VERSION 5.8 ;
BUSBITCHARS "[]" ;
DIVIDERCHAR "/" ;
MANUFACTURINGGRID 0.05 ;

UNITS
    DATABASE MICRONS 1000 ;
END UNITS

SITE CoreSite
    CLASS CORE ;
    SIZE 5.400 BY 64.800 ;
END CoreSite

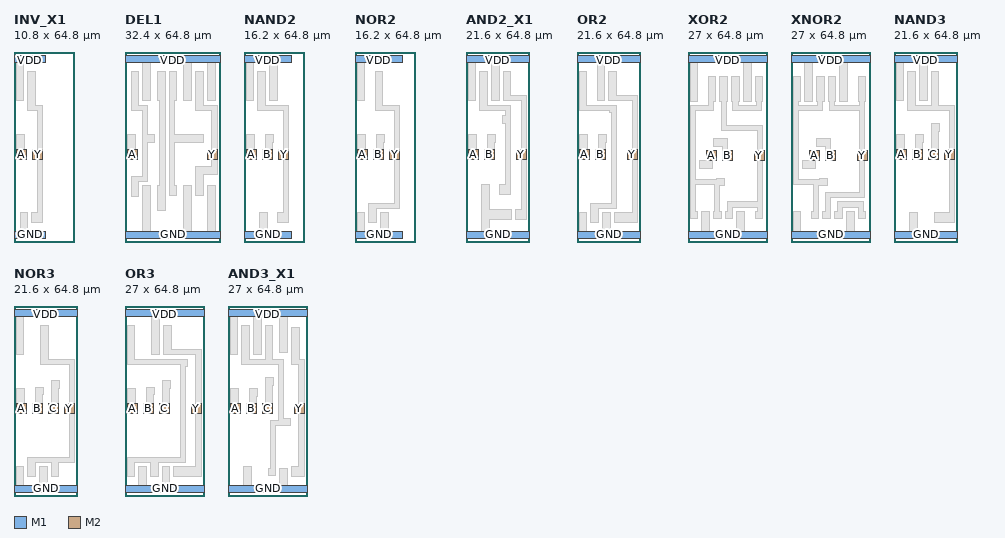
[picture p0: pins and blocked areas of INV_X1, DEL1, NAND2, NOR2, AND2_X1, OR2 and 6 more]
MACRO INV_X1
    CLASS CORE ;
    FOREIGN INV_X1 0.0 0.0 ;
    ORIGIN 0.0 0.0 ;
    SIZE 10.800 BY 64.800 ;
    SITE CoreSite ;

    PIN GND
        DIRECTION INOUT ;
        USE GROUND ;
        PORT
            LAYER M1 ;
                RECT 0.000 1.100 10.800 3.700 ;
        END
    END GND

    PIN VDD
        DIRECTION INOUT ;
        USE POWER ;
        PORT
            LAYER M1 ;
                RECT 0.000 61.100 10.800 63.700 ;
        END
    END VDD

    PIN A
        DIRECTION INPUT ;
        USE SIGNAL ;
        PORT
            LAYER M2 ;
                RECT 1.000 28.000 4.400 31.400 ;
        END
    END A

    PIN Y
        DIRECTION OUTPUT ;
        USE SIGNAL ;
        PORT
            LAYER M2 ;
                RECT 6.400 28.000 9.800 31.400 ;
        END
    END Y

    OBS
        LAYER M1 ;
            POLYGON 2.100 3.700  2.100 9.900  4.700 9.900  4.700 3.700 ;
            POLYGON 1.000 28.000  1.000 36.500  3.600 36.500  3.600 31.400  4.400 31.400  4.400 28.000 ;
            POLYGON 6.100 6.500  6.100 9.900  8.000 9.900  8.000 28.000  6.400 28.000  6.400 31.400  8.000 31.400  8.000 44.900  4.700 44.900  4.700 58.300  7.300 58.300  7.300 46.700  9.800 46.700  9.800 6.500 ;
            POLYGON 0.700 48.100  0.700 61.100  3.300 61.100  3.300 48.100 ;
    END

END INV_X1
MACRO DEL1
    CLASS CORE ;
    FOREIGN DEL1 0.0 0.0 ;
    ORIGIN 0.0 0.0 ;
    SIZE 32.400 BY 64.800 ;
    SITE CoreSite ;

    PIN GND
        DIRECTION INOUT ;
        USE GROUND ;
        PORT
            LAYER M1 ;
                RECT 0.000 1.100 32.400 3.700 ;
        END
    END GND

    PIN VDD
        DIRECTION INOUT ;
        USE POWER ;
        PORT
            LAYER M1 ;
                RECT 0.000 61.100 32.400 63.700 ;
        END
    END VDD

    PIN A
        DIRECTION INPUT ;
        USE SIGNAL ;
        PORT
            LAYER M2 ;
                RECT 1.000 28.000 4.400 31.400 ;
        END
    END A

    PIN Y
        DIRECTION OUTPUT ;
        USE SIGNAL ;
        PORT
            LAYER M2 ;
                RECT 28.000 28.000 31.400 31.400 ;
        END
    END Y

    OBS
        LAYER M1 ;
            POLYGON 6.100 3.700  6.100 19.100  8.700 19.100  8.700 3.700 ;
            POLYGON 20.100 3.700  20.100 19.100  22.700 19.100  22.700 3.700 ;
            POLYGON 28.100 3.700  28.100 19.100  30.700 19.100  30.700 3.700 ;
            POLYGON 1.000 28.000  1.000 36.500  3.600 36.500  3.600 31.400  4.400 31.400  4.400 28.000 ;
            POLYGON 2.100 15.500  2.100 22.300  6.000 22.300  6.000 44.900  2.100 44.900  2.100 58.300  4.700 58.300  4.700 46.700  7.800 46.700  7.800 36.500  10.100 36.500  10.100 33.900  7.800 33.900  7.800 20.500  4.700 20.500  4.700 15.500 ;
            POLYGON 11.100 10.700  11.100 19.100  11.900 19.100  11.900 48.100  11.100 48.100  11.100 58.300  13.700 58.300  13.700 10.700 ;
            POLYGON 15.100 15.700  15.100 58.300  17.700 58.300  17.700 48.100  16.900 48.100  16.900 36.500  26.700 36.500  26.700 33.900  16.900 33.900  16.900 19.100  17.700 19.100  17.700 15.700 ;
            POLYGON 24.100 15.700  24.100 25.800  29.600 25.800  29.600 28.000  28.000 28.000  28.000 31.400  29.600 31.400  29.600 44.900  24.100 44.900  24.100 58.300  26.700 58.300  26.700 46.700  31.400 46.700  31.400 22.900  26.700 22.900  26.700 15.700 ;
            POLYGON 6.100 48.100  6.100 61.100  8.700 61.100  8.700 48.100 ;
            POLYGON 20.100 48.100  20.100 61.100  22.700 61.100  22.700 48.100 ;
            POLYGON 28.100 48.100  28.100 61.100  30.700 61.100  30.700 48.100 ;
    END

END DEL1
MACRO NAND2
    CLASS CORE ;
    FOREIGN NAND2 0.0 0.0 ;
    ORIGIN 0.0 0.0 ;
    SIZE 16.200 BY 64.800 ;
    SITE CoreSite ;

    PIN GND
        DIRECTION INOUT ;
        USE GROUND ;
        PORT
            LAYER M1 ;
                RECT 0.000 1.100 16.200 3.700 ;
        END
    END GND

    PIN VDD
        DIRECTION INOUT ;
        USE POWER ;
        PORT
            LAYER M1 ;
                RECT 0.000 61.100 16.200 63.700 ;
        END
    END VDD

    PIN A
        DIRECTION INPUT ;
        USE SIGNAL ;
        PORT
            LAYER M2 ;
                RECT 1.000 28.000 4.400 31.400 ;
        END
    END A

    PIN B
        DIRECTION INPUT ;
        USE SIGNAL ;
        PORT
            LAYER M2 ;
                RECT 6.400 28.000 9.800 31.400 ;
        END
    END B

    PIN Y
        DIRECTION OUTPUT ;
        USE SIGNAL ;
        PORT
            LAYER M2 ;
                RECT 11.800 28.000 15.200 31.400 ;
        END
    END Y

    OBS
        LAYER M1 ;
            POLYGON 5.300 3.700  5.300 9.900  7.900 9.900  7.900 3.700 ;
            POLYGON 1.000 28.000  1.000 36.500  3.600 36.500  3.600 31.400  4.400 31.400  4.400 28.000 ;
            POLYGON 6.400 28.000  6.400 31.400  7.500 31.400  7.500 36.500  10.100 36.500  10.100 33.900  9.800 33.900  9.800 28.000 ;
            POLYGON 11.500 6.500  11.500 9.900  13.400 9.900  13.400 28.000  11.800 28.000  11.800 31.400  13.400 31.400  13.400 44.900  4.700 44.900  4.700 58.300  7.300 58.300  7.300 46.700  15.200 46.700  15.200 6.500 ;
            POLYGON 0.700 48.100  0.700 61.100  3.300 61.100  3.300 48.100 ;
            POLYGON 8.700 48.100  8.700 61.100  11.300 61.100  11.300 48.100 ;
    END

END NAND2
MACRO NOR2
    CLASS CORE ;
    FOREIGN NOR2 0.0 0.0 ;
    ORIGIN 0.0 0.0 ;
    SIZE 16.200 BY 64.800 ;
    SITE CoreSite ;

    PIN GND
        DIRECTION INOUT ;
        USE GROUND ;
        PORT
            LAYER M1 ;
                RECT 0.000 1.100 16.200 3.700 ;
        END
    END GND

    PIN VDD
        DIRECTION INOUT ;
        USE POWER ;
        PORT
            LAYER M1 ;
                RECT 0.000 61.100 16.200 63.700 ;
        END
    END VDD

    PIN A
        DIRECTION INPUT ;
        USE SIGNAL ;
        PORT
            LAYER M2 ;
                RECT 1.000 28.000 4.400 31.400 ;
        END
    END A

    PIN B
        DIRECTION INPUT ;
        USE SIGNAL ;
        PORT
            LAYER M2 ;
                RECT 6.400 28.000 9.800 31.400 ;
        END
    END B

    PIN Y
        DIRECTION OUTPUT ;
        USE SIGNAL ;
        PORT
            LAYER M2 ;
                RECT 11.800 28.000 15.200 31.400 ;
        END
    END Y

    OBS
        LAYER M1 ;
            POLYGON 0.700 3.700  0.700 9.900  3.300 9.900  3.300 3.700 ;
            POLYGON 8.700 3.700  8.700 9.900  11.300 9.900  11.300 3.700 ;
            POLYGON 1.000 28.000  1.000 36.500  3.600 36.500  3.600 31.400  4.400 31.400  4.400 28.000 ;
            POLYGON 6.400 28.000  6.400 31.400  7.500 31.400  7.500 36.500  10.100 36.500  10.100 33.900  9.800 33.900  9.800 28.000 ;
            POLYGON 4.700 6.500  4.700 13.200  13.400 13.200  13.400 28.000  11.800 28.000  11.800 31.400  13.400 31.400  13.400 44.900  6.900 44.900  6.900 58.300  9.500 58.300  9.500 46.700  15.200 46.700  15.200 11.400  7.300 11.400  7.300 6.500 ;
            POLYGON 0.700 48.100  0.700 61.100  3.300 61.100  3.300 48.100 ;
    END

END NOR2
MACRO AND2_X1
    CLASS CORE ;
    FOREIGN AND2_X1 0.0 0.0 ;
    ORIGIN 0.0 0.0 ;
    SIZE 21.600 BY 64.800 ;
    SITE CoreSite ;

    PIN GND
        DIRECTION INOUT ;
        USE GROUND ;
        PORT
            LAYER M1 ;
                RECT 0.000 1.100 21.600 3.700 ;
        END
    END GND

    PIN VDD
        DIRECTION INOUT ;
        USE POWER ;
        PORT
            LAYER M1 ;
                RECT 0.000 61.100 21.600 63.700 ;
        END
    END VDD

    PIN A
        DIRECTION INPUT ;
        USE SIGNAL ;
        PORT
            LAYER M2 ;
                RECT 1.000 28.000 4.400 31.400 ;
        END
    END A

    PIN B
        DIRECTION INPUT ;
        USE SIGNAL ;
        PORT
            LAYER M2 ;
                RECT 6.400 28.000 9.800 31.400 ;
        END
    END B

    PIN Y
        DIRECTION OUTPUT ;
        USE SIGNAL ;
        PORT
            LAYER M2 ;
                RECT 17.200 28.000 20.600 31.400 ;
        END
    END Y

    OBS
        LAYER M1 ;
            POLYGON 5.300 3.700  5.300 19.600  7.900 19.600  7.900 11.100  15.500 11.100  15.500 7.700  7.900 7.700  7.900 3.700 ;
            POLYGON 1.000 28.000  1.000 36.500  3.600 36.500  3.600 31.400  4.400 31.400  4.400 28.000 ;
            POLYGON 6.400 28.000  6.400 31.400  7.500 31.400  7.500 36.500  10.100 36.500  10.100 33.900  9.800 33.900  9.800 28.000 ;
            POLYGON 11.500 16.200  11.500 19.600  13.400 19.600  13.400 40.400  12.600 40.400  12.600 43.000  13.400 43.000  13.400 44.900  4.700 44.900  4.700 58.300  7.300 58.300  7.300 46.700  15.200 46.700  15.200 16.200 ;
            POLYGON 16.900 7.700  16.900 11.100  18.800 11.100  18.800 28.000  17.200 28.000  17.200 31.400  18.800 31.400  18.800 48.100  12.700 48.100  12.700 58.300  15.300 58.300  15.300 50.000  20.600 50.000  20.600 7.700 ;
            POLYGON 0.700 48.100  0.700 61.100  3.300 61.100  3.300 48.100 ;
            POLYGON 8.700 48.100  8.700 61.100  11.300 61.100  11.300 48.100 ;
    END

END AND2_X1
MACRO OR2
    CLASS CORE ;
    FOREIGN OR2 0.0 0.0 ;
    ORIGIN 0.0 0.0 ;
    SIZE 21.600 BY 64.800 ;
    SITE CoreSite ;

    PIN GND
        DIRECTION INOUT ;
        USE GROUND ;
        PORT
            LAYER M1 ;
                RECT 0.000 1.100 21.600 3.700 ;
        END
    END GND

    PIN VDD
        DIRECTION INOUT ;
        USE POWER ;
        PORT
            LAYER M1 ;
                RECT 0.000 61.100 21.600 63.700 ;
        END
    END VDD

    PIN A
        DIRECTION INPUT ;
        USE SIGNAL ;
        PORT
            LAYER M2 ;
                RECT 1.000 28.000 4.400 31.400 ;
        END
    END A

    PIN B
        DIRECTION INPUT ;
        USE SIGNAL ;
        PORT
            LAYER M2 ;
                RECT 6.400 28.000 9.800 31.400 ;
        END
    END B

    PIN Y
        DIRECTION OUTPUT ;
        USE SIGNAL ;
        PORT
            LAYER M2 ;
                RECT 17.200 28.000 20.600 31.400 ;
        END
    END Y

    OBS
        LAYER M1 ;
            POLYGON 0.700 3.700  0.700 9.900  3.300 9.900  3.300 3.700 ;
            POLYGON 8.700 3.700  8.700 9.900  11.300 9.900  11.300 3.700 ;
            POLYGON 1.000 28.000  1.000 36.500  3.600 36.500  3.600 31.400  4.400 31.400  4.400 28.000 ;
            POLYGON 6.400 28.000  6.400 31.400  7.500 31.400  7.500 36.500  10.100 36.500  10.100 33.900  9.800 33.900  9.800 28.000 ;
            POLYGON 4.700 6.500  4.700 13.200  11.800 13.200  11.800 44.100  11.000 44.100  11.000 44.900  0.700 44.900  0.700 58.300  3.300 58.300  3.300 46.700  13.600 46.700  13.600 11.400  7.300 11.400  7.300 6.500 ;
            POLYGON 12.700 6.500  12.700 9.900  18.800 9.900  18.800 28.000  17.200 28.000  17.200 31.400  18.800 31.400  18.800 48.100  10.900 48.100  10.900 58.300  13.500 58.300  13.500 49.900  20.600 49.900  20.600 6.500 ;
            POLYGON 6.900 48.100  6.900 61.100  9.500 61.100  9.500 48.100 ;
    END

END OR2
MACRO XOR2
    CLASS CORE ;
    FOREIGN XOR2 0.0 0.0 ;
    ORIGIN 0.0 0.0 ;
    SIZE 27.000 BY 64.800 ;
    SITE CoreSite ;

    PIN GND
        DIRECTION INOUT ;
        USE GROUND ;
        PORT
            LAYER M1 ;
                RECT 0.000 1.100 27.000 3.700 ;
        END
    END GND

    PIN VDD
        DIRECTION INOUT ;
        USE POWER ;
        PORT
            LAYER M1 ;
                RECT 0.000 61.100 27.000 63.700 ;
        END
    END VDD

    PIN A
        DIRECTION INPUT ;
        USE SIGNAL ;
        PORT
            LAYER M2 ;
                RECT 6.400 27.900 9.800 31.300 ;
        END
    END A

    PIN B
        DIRECTION INPUT ;
        USE SIGNAL ;
        PORT
            LAYER M2 ;
                RECT 11.800 27.900 15.200 31.300 ;
        END
    END B

    PIN Y
        DIRECTION OUTPUT ;
        USE SIGNAL ;
        PORT
            LAYER M2 ;
                RECT 22.600 27.900 26.000 31.300 ;
        END
    END Y

    OBS
        LAYER M1 ;
            POLYGON 4.700 3.700  4.700 10.500  7.300 10.500  7.300 3.700 ;
            POLYGON 16.700 3.700  16.700 10.500  19.300 10.500  19.300 3.700 ;
            POLYGON 3.900 25.100  3.900 27.700  6.400 27.700  6.400 31.300  9.800 31.300  9.800 27.900  8.200 27.900  8.200 25.100 ;
            POLYGON 11.800 27.900  11.800 32.700  8.700 32.700  8.700 35.300  13.600 35.300  13.600 31.300  15.200 31.300  15.200 27.900 ;
            POLYGON 0.700 7.900  0.700 46.500  6.900 46.500  6.900 56.500  9.500 56.500  9.500 47.900  8.700 47.900  8.700 44.700  2.500 44.700  2.500 21.400  9.700 21.400  9.700 21.700  12.300 21.700  12.300 19.100  10.900 19.100  10.900 10.500  11.300 10.500  11.300 7.900  8.700 7.900  8.700 10.500  9.100 10.500  9.100 19.600  2.500 19.600  2.500 10.500  3.300 10.500  3.300 7.900 ;
            POLYGON 12.700 7.900  12.700 10.500  13.500 10.500  13.500 13.700  23.600 13.700  23.600 27.900  22.600 27.900  22.600 31.300  23.600 31.300  23.600 38.100  11.300 38.100  11.300 47.900  10.900 47.900  10.900 56.500  13.500 56.500  13.500 47.900  13.100 47.900  13.100 39.900  25.400 39.900  25.400 31.300  26.000 31.300  26.000 27.900  25.400 27.900  25.400 10.500  25.500 10.500  25.500 7.900  22.900 7.900  22.900 10.500  23.600 10.500  23.600 11.900  15.300 11.900  15.300 7.900 ;
            POLYGON 15.300 44.700  15.300 47.900  14.900 47.900  14.900 56.500  17.500 56.500  17.500 47.900  17.100 47.900  17.100 46.500  23.300 46.500  23.300 47.900  22.900 47.900  22.900 56.500  25.500 56.500  25.500 47.900  25.100 47.900  25.100 44.700 ;
            POLYGON 0.700 47.900  0.700 61.100  3.300 61.100  3.300 47.900 ;
            POLYGON 18.900 47.900  18.900 61.100  21.500 61.100  21.500 47.900 ;
    END

END XOR2
MACRO XNOR2
    CLASS CORE ;
    FOREIGN XNOR2 0.0 0.0 ;
    ORIGIN 0.0 0.0 ;
    SIZE 27.000 BY 64.800 ;
    SITE CoreSite ;

    PIN GND
        DIRECTION INOUT ;
        USE GROUND ;
        PORT
            LAYER M1 ;
                RECT 0.000 1.100 27.000 3.700 ;
        END
    END GND

    PIN VDD
        DIRECTION INOUT ;
        USE POWER ;
        PORT
            LAYER M1 ;
                RECT 0.000 61.100 27.000 63.700 ;
        END
    END VDD

    PIN A
        DIRECTION INPUT ;
        USE SIGNAL ;
        PORT
            LAYER M2 ;
                RECT 6.400 27.900 9.800 31.300 ;
        END
    END A

    PIN B
        DIRECTION INPUT ;
        USE SIGNAL ;
        PORT
            LAYER M2 ;
                RECT 11.800 27.900 15.200 31.300 ;
        END
    END B

    PIN Y
        DIRECTION OUTPUT ;
        USE SIGNAL ;
        PORT
            LAYER M2 ;
                RECT 22.600 27.900 26.000 31.300 ;
        END
    END Y

    OBS
        LAYER M1 ;
            POLYGON 0.700 3.700  0.700 10.500  3.300 10.500  3.300 3.700 ;
            POLYGON 18.900 3.700  18.900 10.500  21.500 10.500  21.500 3.700 ;
            POLYGON 14.900 7.900  14.900 10.500  15.700 10.500  15.700 13.700  24.700 13.700  24.700 10.500  25.500 10.500  25.500 7.900  22.900 7.900  22.900 11.900  17.500 11.900  17.500 7.900 ;
            POLYGON 3.900 25.100  3.900 27.700  6.400 27.700  6.400 31.300  9.800 31.300  9.800 27.900  8.200 27.900  8.200 25.100 ;
            POLYGON 11.800 27.900  11.800 32.700  8.700 32.700  8.700 35.300  13.600 35.300  13.600 31.300  15.200 31.300  15.200 27.900 ;
            POLYGON 6.900 7.900  6.900 10.500  7.700 10.500  7.700 19.600  0.700 19.600  0.700 56.500  3.300 56.500  3.300 47.900  2.500 47.900  2.500 46.500  9.100 46.500  9.100 47.900  8.700 47.900  8.700 56.500  11.300 56.500  11.300 47.900  10.900 47.900  10.900 44.700  2.500 44.700  2.500 21.400  9.700 21.400  9.700 21.700  12.300 21.700  12.300 19.100  9.500 19.100  9.500 7.900 ;
            POLYGON 10.900 7.900  10.900 10.500  11.700 10.500  11.700 16.900  23.300 16.900  23.300 27.900  22.600 27.900  22.600 31.300  23.300 31.300  23.300 44.700  13.100 44.700  13.100 47.900  12.700 47.900  12.700 56.500  15.300 56.500  15.300 47.900  14.900 47.900  14.900 46.500  23.300 46.500  23.300 47.900  22.900 47.900  22.900 56.500  25.500 56.500  25.500 47.900  25.100 47.900  25.100 31.300  26.000 31.300  26.000 27.900  25.100 27.900  25.100 15.100  13.500 15.100  13.500 7.900 ;
            POLYGON 4.700 47.900  4.700 61.100  7.300 61.100  7.300 47.900 ;
            POLYGON 16.700 47.900  16.700 61.100  19.300 61.100  19.300 47.900 ;
    END

END XNOR2
MACRO NAND3
    CLASS CORE ;
    FOREIGN NAND3 0.0 0.0 ;
    ORIGIN 0.0 0.0 ;
    SIZE 21.600 BY 64.800 ;
    SITE CoreSite ;

    PIN GND
        DIRECTION INOUT ;
        USE GROUND ;
        PORT
            LAYER M1 ;
                RECT 0.000 1.100 21.600 3.700 ;
        END
    END GND

    PIN VDD
        DIRECTION INOUT ;
        USE POWER ;
        PORT
            LAYER M1 ;
                RECT 0.000 61.100 21.600 63.700 ;
        END
    END VDD

    PIN A
        DIRECTION INPUT ;
        USE SIGNAL ;
        PORT
            LAYER M2 ;
                RECT 1.000 28.000 4.400 31.400 ;
        END
    END A

    PIN B
        DIRECTION INPUT ;
        USE SIGNAL ;
        PORT
            LAYER M2 ;
                RECT 6.400 28.000 9.800 31.400 ;
        END
    END B

    PIN C
        DIRECTION INPUT ;
        USE SIGNAL ;
        PORT
            LAYER M2 ;
                RECT 11.800 28.000 15.200 31.400 ;
        END
    END C

    PIN Y
        DIRECTION OUTPUT ;
        USE SIGNAL ;
        PORT
            LAYER M2 ;
                RECT 17.200 28.000 20.600 31.400 ;
        END
    END Y

    OBS
        LAYER M1 ;
            POLYGON 5.300 3.700  5.300 9.900  7.900 9.900  7.900 3.700 ;
            POLYGON 1.000 28.000  1.000 36.500  3.600 36.500  3.600 31.400  4.400 31.400  4.400 28.000 ;
            POLYGON 6.400 28.000  6.400 31.400  7.500 31.400  7.500 36.500  10.100 36.500  10.100 33.900  9.800 33.900  9.800 28.000 ;
            POLYGON 11.800 28.000  11.800 31.400  12.900 31.400  12.900 40.300  15.500 40.300  15.500 37.700  15.200 37.700  15.200 28.000 ;
            POLYGON 13.700 6.500  13.700 9.900  18.800 9.900  18.800 28.000  17.200 28.000  17.200 31.400  18.800 31.400  18.800 44.900  4.700 44.900  4.700 58.300  7.300 58.300  7.300 46.700  12.700 46.700  12.700 58.300  15.300 58.300  15.300 46.700  20.600 46.700  20.600 6.500 ;
            POLYGON 0.700 48.100  0.700 61.100  3.300 61.100  3.300 48.100 ;
            POLYGON 8.700 48.100  8.700 61.100  11.300 61.100  11.300 48.100 ;
    END

END NAND3
MACRO NOR3
    CLASS CORE ;
    FOREIGN NOR3 0.0 0.0 ;
    ORIGIN 0.0 0.0 ;
    SIZE 21.600 BY 64.800 ;
    SITE CoreSite ;

    PIN GND
        DIRECTION INOUT ;
        USE GROUND ;
        PORT
            LAYER M1 ;
                RECT 0.000 1.100 21.600 3.700 ;
        END
    END GND

    PIN VDD
        DIRECTION INOUT ;
        USE POWER ;
        PORT
            LAYER M1 ;
                RECT 0.000 61.100 21.600 63.700 ;
        END
    END VDD

    PIN A
        DIRECTION INPUT ;
        USE SIGNAL ;
        PORT
            LAYER M2 ;
                RECT 1.000 28.000 4.400 31.400 ;
        END
    END A

    PIN B
        DIRECTION INPUT ;
        USE SIGNAL ;
        PORT
            LAYER M2 ;
                RECT 6.400 28.000 9.800 31.400 ;
        END
    END B

    PIN C
        DIRECTION INPUT ;
        USE SIGNAL ;
        PORT
            LAYER M2 ;
                RECT 11.800 28.000 15.200 31.400 ;
        END
    END C

    PIN Y
        DIRECTION OUTPUT ;
        USE SIGNAL ;
        PORT
            LAYER M2 ;
                RECT 17.200 28.000 20.600 31.400 ;
        END
    END Y

    OBS
        LAYER M1 ;
            POLYGON 0.700 3.700  0.700 9.900  3.300 9.900  3.300 3.700 ;
            POLYGON 8.700 3.700  8.700 9.900  11.300 9.900  11.300 3.700 ;
            POLYGON 1.000 28.000  1.000 36.500  3.600 36.500  3.600 31.400  4.400 31.400  4.400 28.000 ;
            POLYGON 6.400 28.000  6.400 31.400  7.500 31.400  7.500 37.100  10.100 37.100  10.100 34.500  9.800 34.500  9.800 28.000 ;
            POLYGON 11.800 28.000  11.800 31.400  12.900 31.400  12.900 39.300  15.500 39.300  15.500 36.700  15.200 36.700  15.200 28.000 ;
            POLYGON 4.700 6.500  4.700 13.200  18.800 13.200  18.800 28.000  17.200 28.000  17.200 31.400  18.800 31.400  18.800 44.900  9.100 44.900  9.100 58.300  11.700 58.300  11.700 46.700  20.600 46.700  20.600 11.400  15.300 11.400  15.300 6.500  12.700 6.500  12.700 11.400  7.300 11.400  7.300 6.500 ;
            POLYGON 0.700 48.100  0.700 61.100  3.300 61.100  3.300 48.100 ;
    END

END NOR3
MACRO OR3
    CLASS CORE ;
    FOREIGN OR3 0.0 0.0 ;
    ORIGIN 0.0 0.0 ;
    SIZE 27.000 BY 64.800 ;
    SITE CoreSite ;

    PIN GND
        DIRECTION INOUT ;
        USE GROUND ;
        PORT
            LAYER M1 ;
                RECT 0.000 1.100 27.000 3.700 ;
        END
    END GND

    PIN VDD
        DIRECTION INOUT ;
        USE POWER ;
        PORT
            LAYER M1 ;
                RECT 0.000 61.100 27.000 63.700 ;
        END
    END VDD

    PIN A
        DIRECTION INPUT ;
        USE SIGNAL ;
        PORT
            LAYER M2 ;
                RECT 1.000 28.000 4.400 31.400 ;
        END
    END A

    PIN B
        DIRECTION INPUT ;
        USE SIGNAL ;
        PORT
            LAYER M2 ;
                RECT 6.400 28.000 9.800 31.400 ;
        END
    END B

    PIN C
        DIRECTION INPUT ;
        USE SIGNAL ;
        PORT
            LAYER M2 ;
                RECT 11.800 28.000 15.200 31.400 ;
        END
    END C

    PIN Y
        DIRECTION OUTPUT ;
        USE SIGNAL ;
        PORT
            LAYER M2 ;
                RECT 22.600 28.000 26.000 31.400 ;
        END
    END Y

    OBS
        LAYER M1 ;
            POLYGON 4.700 3.700  4.700 9.900  7.300 9.900  7.300 3.700 ;
            POLYGON 12.700 3.700  12.700 9.900  15.300 9.900  15.300 3.700 ;
            POLYGON 1.000 28.000  1.000 36.500  3.600 36.500  3.600 31.400  4.400 31.400  4.400 28.000 ;
            POLYGON 6.400 28.000  6.400 31.400  7.500 31.400  7.500 37.100  10.100 37.100  10.100 34.500  9.800 34.500  9.800 28.000 ;
            POLYGON 11.800 28.000  11.800 31.400  12.900 31.400  12.900 39.300  15.500 39.300  15.500 36.700  15.200 36.700  15.200 28.000 ;
            POLYGON 0.700 6.500  0.700 13.200  18.800 13.200  18.800 44.900  0.700 44.900  0.700 58.300  3.300 58.300  3.300 46.700  21.400 46.700  21.400 44.000  20.600 44.000  20.600 11.400  11.300 11.400  11.300 6.500  8.700 6.500  8.700 11.400  3.300 11.400  3.300 6.500 ;
            POLYGON 16.700 6.500  16.700 9.900  24.200 9.900  24.200 28.000  22.600 28.000  22.600 31.400  24.200 31.400  24.200 48.100  13.100 48.100  13.100 58.300  15.700 58.300  15.700 49.900  26.000 49.900  26.000 6.500 ;
            POLYGON 9.100 48.100  9.100 61.100  11.700 61.100  11.700 48.100 ;
    END

END OR3
MACRO AND3_X1
    CLASS CORE ;
    FOREIGN AND3_X1 0.0 0.0 ;
    ORIGIN 0.0 0.0 ;
    SIZE 27.000 BY 64.800 ;
    SITE CoreSite ;

    PIN GND
        DIRECTION INOUT ;
        USE GROUND ;
        PORT
            LAYER M1 ;
                RECT 0.000 1.100 27.000 3.700 ;
        END
    END GND

    PIN VDD
        DIRECTION INOUT ;
        USE POWER ;
        PORT
            LAYER M1 ;
                RECT 0.000 61.100 27.000 63.700 ;
        END
    END VDD

    PIN A
        DIRECTION INPUT ;
        USE SIGNAL ;
        PORT
            LAYER M2 ;
                RECT 1.000 28.000 4.400 31.400 ;
        END
    END A

    PIN B
        DIRECTION INPUT ;
        USE SIGNAL ;
        PORT
            LAYER M2 ;
                RECT 6.400 28.000 9.800 31.400 ;
        END
    END B

    PIN C
        DIRECTION INPUT ;
        USE SIGNAL ;
        PORT
            LAYER M2 ;
                RECT 11.800 28.000 15.200 31.400 ;
        END
    END C

    PIN Y
        DIRECTION OUTPUT ;
        USE SIGNAL ;
        PORT
            LAYER M2 ;
                RECT 22.600 28.000 26.000 31.400 ;
        END
    END Y

    OBS
        LAYER M1 ;
            POLYGON 17.700 3.700  17.700 9.500  20.300 9.500  20.300 3.700 ;
            POLYGON 5.300 3.700  5.300 9.900  7.900 9.900  7.900 3.700 ;
            POLYGON 1.000 28.000  1.000 36.500  3.600 36.500  3.600 31.400  4.400 31.400  4.400 28.000 ;
            POLYGON 6.400 28.000  6.400 31.400  7.500 31.400  7.500 36.500  10.100 36.500  10.100 33.900  9.800 33.900  9.800 28.000 ;
            POLYGON 11.800 28.000  11.800 31.400  12.900 31.400  12.900 40.300  15.500 40.300  15.500 37.700  15.200 37.700  15.200 28.000 ;
            POLYGON 21.700 6.500  21.700 9.900  24.200 9.900  24.200 28.000  22.600 28.000  22.600 31.400  24.200 31.400  24.200 44.900  21.700 44.900  21.700 57.500  24.300 57.500  24.300 46.700  26.000 46.700  26.000 6.500 ;
            POLYGON 13.700 6.900  13.700 9.500  14.500 9.500  14.500 25.800  17.100 25.800  17.100 44.900  4.700 44.900  4.700 58.300  7.300 58.300  7.300 46.700  12.700 46.700  12.700 58.300  15.300 58.300  15.300 46.700  18.900 46.700  18.900 26.600  21.200 26.600  21.200 24.000  16.300 24.000  16.300 6.900 ;
            POLYGON 0.700 48.100  0.700 61.100  3.300 61.100  3.300 48.100 ;
            POLYGON 8.700 48.100  8.700 61.100  11.300 61.100  11.300 48.100 ;
            POLYGON 17.700 48.900  17.700 61.100  20.300 61.100  20.300 48.900 ;
    END

END AND3_X1
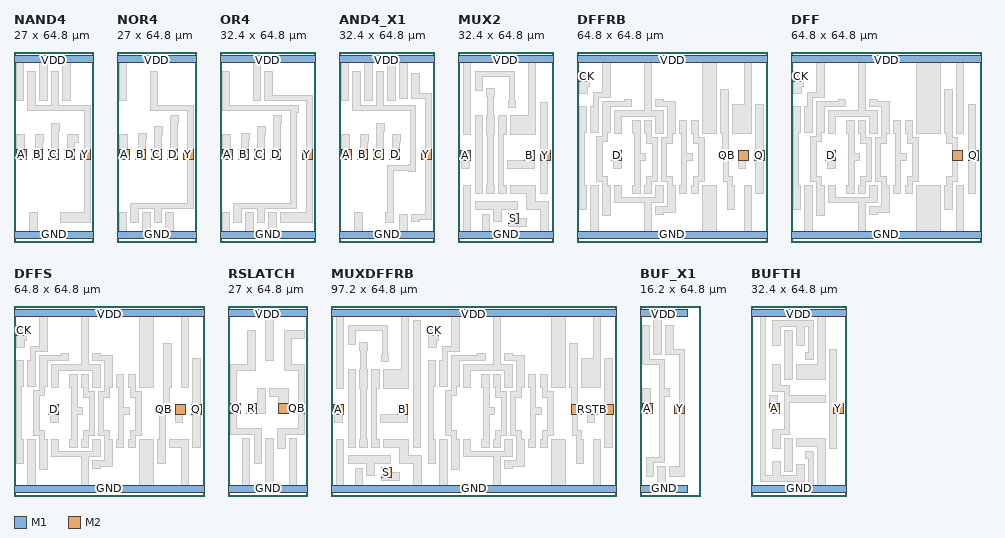
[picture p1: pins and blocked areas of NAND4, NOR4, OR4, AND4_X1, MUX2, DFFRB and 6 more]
MACRO NAND4
    CLASS CORE ;
    FOREIGN NAND4 0.0 0.0 ;
    ORIGIN 0.0 0.0 ;
    SIZE 27.000 BY 64.800 ;
    SITE CoreSite ;

    PIN GND
        DIRECTION INOUT ;
        USE GROUND ;
        PORT
            LAYER M1 ;
                RECT 0.000 1.100 27.000 3.700 ;
        END
    END GND

    PIN VDD
        DIRECTION INOUT ;
        USE POWER ;
        PORT
            LAYER M1 ;
                RECT 0.000 61.100 27.000 63.700 ;
        END
    END VDD

    PIN A
        DIRECTION INPUT ;
        USE SIGNAL ;
        PORT
            LAYER M2 ;
                RECT 1.000 28.000 4.400 31.400 ;
        END
    END A

    PIN B
        DIRECTION INPUT ;
        USE SIGNAL ;
        PORT
            LAYER M2 ;
                RECT 6.400 28.000 9.800 31.400 ;
        END
    END B

    PIN C
        DIRECTION INPUT ;
        USE SIGNAL ;
        PORT
            LAYER M2 ;
                RECT 11.800 28.000 15.200 31.400 ;
        END
    END C

    PIN D
        DIRECTION INPUT ;
        USE SIGNAL ;
        PORT
            LAYER M2 ;
                RECT 17.200 28.000 20.600 31.400 ;
        END
    END D

    PIN Y
        DIRECTION OUTPUT ;
        USE SIGNAL ;
        PORT
            LAYER M2 ;
                RECT 22.600 28.000 26.000 31.400 ;
        END
    END Y

    OBS
        LAYER M1 ;
            POLYGON 5.300 3.700  5.300 9.900  7.900 9.900  7.900 3.700 ;
            POLYGON 1.000 28.000  1.000 36.500  3.600 36.500  3.600 31.400  4.400 31.400  4.400 28.000 ;
            POLYGON 6.400 28.000  6.400 31.400  7.500 31.400  7.500 36.500  10.100 36.500  10.100 33.900  9.800 33.900  9.800 28.000 ;
            POLYGON 17.200 28.000  17.200 31.400  18.300 31.400  18.300 36.500  22.100 36.500  22.100 33.900  20.600 33.900  20.600 28.000 ;
            POLYGON 11.800 28.000  11.800 31.400  12.900 31.400  12.900 40.300  15.500 40.300  15.500 37.700  15.200 37.700  15.200 28.000 ;
            POLYGON 15.900 6.500  15.900 9.900  24.200 9.900  24.200 28.000  22.600 28.000  22.600 31.400  24.200 31.400  24.200 44.900  4.700 44.900  4.700 58.300  7.300 58.300  7.300 46.700  12.700 46.700  12.700 58.300  15.300 58.300  15.300 46.700  26.000 46.700  26.000 6.500 ;
            POLYGON 0.700 48.100  0.700 61.100  3.300 61.100  3.300 48.100 ;
            POLYGON 8.700 48.100  8.700 61.100  11.300 61.100  11.300 48.100 ;
            POLYGON 16.700 48.100  16.700 61.100  19.300 61.100  19.300 48.100 ;
    END

END NAND4
MACRO NOR4
    CLASS CORE ;
    FOREIGN NOR4 0.0 0.0 ;
    ORIGIN 0.0 0.0 ;
    SIZE 27.000 BY 64.800 ;
    SITE CoreSite ;

    PIN GND
        DIRECTION INOUT ;
        USE GROUND ;
        PORT
            LAYER M1 ;
                RECT 0.000 1.100 27.000 3.700 ;
        END
    END GND

    PIN VDD
        DIRECTION INOUT ;
        USE POWER ;
        PORT
            LAYER M1 ;
                RECT 0.000 61.100 27.000 63.700 ;
        END
    END VDD

    PIN A
        DIRECTION INPUT ;
        USE SIGNAL ;
        PORT
            LAYER M2 ;
                RECT 1.000 28.000 4.400 31.400 ;
        END
    END A

    PIN B
        DIRECTION INPUT ;
        USE SIGNAL ;
        PORT
            LAYER M2 ;
                RECT 6.400 28.000 9.800 31.400 ;
        END
    END B

    PIN C
        DIRECTION INPUT ;
        USE SIGNAL ;
        PORT
            LAYER M2 ;
                RECT 11.800 28.000 15.200 31.400 ;
        END
    END C

    PIN D
        DIRECTION INPUT ;
        USE SIGNAL ;
        PORT
            LAYER M2 ;
                RECT 17.200 28.000 20.600 31.400 ;
        END
    END D

    PIN Y
        DIRECTION OUTPUT ;
        USE SIGNAL ;
        PORT
            LAYER M2 ;
                RECT 22.600 28.000 26.000 31.400 ;
        END
    END Y

    OBS
        LAYER M1 ;
            POLYGON 0.700 3.700  0.700 9.900  3.300 9.900  3.300 3.700 ;
            POLYGON 8.700 3.700  8.700 9.900  11.300 9.900  11.300 3.700 ;
            POLYGON 16.700 3.700  16.700 9.900  19.300 9.900  19.300 3.700 ;
            POLYGON 1.000 28.000  1.000 36.500  3.600 36.500  3.600 31.400  4.400 31.400  4.400 28.000 ;
            POLYGON 6.400 28.000  6.400 31.400  7.500 31.400  7.500 37.100  10.100 37.100  10.100 34.500  9.800 34.500  9.800 28.000 ;
            POLYGON 11.800 28.000  11.800 31.400  12.900 31.400  12.900 39.300  15.500 39.300  15.500 36.700  15.200 36.700  15.200 28.000 ;
            POLYGON 17.200 28.000  17.200 31.400  18.300 31.400  18.300 43.100  20.900 43.100  20.900 40.500  20.600 40.500  20.600 28.000 ;
            POLYGON 4.700 6.500  4.700 13.200  24.200 13.200  24.200 28.000  22.600 28.000  22.600 31.400  24.200 31.400  24.200 44.900  11.300 44.900  11.300 58.300  13.900 58.300  13.900 46.700  26.000 46.700  26.000 11.400  15.300 11.400  15.300 6.500  12.700 6.500  12.700 11.400  7.300 11.400  7.300 6.500 ;
            POLYGON 0.700 48.100  0.700 61.100  3.300 61.100  3.300 48.100 ;
    END

END NOR4
MACRO OR4
    CLASS CORE ;
    FOREIGN OR4 0.0 0.0 ;
    ORIGIN 0.0 0.0 ;
    SIZE 32.400 BY 64.800 ;
    SITE CoreSite ;

    PIN GND
        DIRECTION INOUT ;
        USE GROUND ;
        PORT
            LAYER M1 ;
                RECT 0.000 1.100 32.400 3.700 ;
        END
    END GND

    PIN VDD
        DIRECTION INOUT ;
        USE POWER ;
        PORT
            LAYER M1 ;
                RECT 0.000 61.100 32.400 63.700 ;
        END
    END VDD

    PIN A
        DIRECTION INPUT ;
        USE SIGNAL ;
        PORT
            LAYER M2 ;
                RECT 1.000 28.000 4.400 31.400 ;
        END
    END A

    PIN B
        DIRECTION INPUT ;
        USE SIGNAL ;
        PORT
            LAYER M2 ;
                RECT 6.400 28.000 9.800 31.400 ;
        END
    END B

    PIN C
        DIRECTION INPUT ;
        USE SIGNAL ;
        PORT
            LAYER M2 ;
                RECT 11.800 28.000 15.200 31.400 ;
        END
    END C

    PIN D
        DIRECTION INPUT ;
        USE SIGNAL ;
        PORT
            LAYER M2 ;
                RECT 17.200 28.000 20.600 31.400 ;
        END
    END D

    PIN Y
        DIRECTION OUTPUT ;
        USE SIGNAL ;
        PORT
            LAYER M2 ;
                RECT 28.000 28.000 31.400 31.400 ;
        END
    END Y

    OBS
        LAYER M1 ;
            POLYGON 0.700 3.700  0.700 9.900  3.300 9.900  3.300 3.700 ;
            POLYGON 8.700 3.700  8.700 9.900  11.300 9.900  11.300 3.700 ;
            POLYGON 16.700 3.700  16.700 9.900  19.300 9.900  19.300 3.700 ;
            POLYGON 1.000 28.000  1.000 36.500  3.600 36.500  3.600 31.400  4.400 31.400  4.400 28.000 ;
            POLYGON 6.400 28.000  6.400 31.400  7.500 31.400  7.500 37.100  10.100 37.100  10.100 34.500  9.800 34.500  9.800 28.000 ;
            POLYGON 11.800 28.000  11.800 31.400  12.900 31.400  12.900 39.300  15.500 39.300  15.500 36.700  15.200 36.700  15.200 28.000 ;
            POLYGON 17.200 28.000  17.200 31.400  18.300 31.400  18.300 43.100  20.900 43.100  20.900 40.500  20.600 40.500  20.600 28.000 ;
            POLYGON 4.700 6.500  4.700 13.200  24.200 13.200  24.200 44.900  0.700 44.900  0.700 58.300  3.300 58.300  3.300 46.700  26.800 46.700  26.800 44.100  26.000 44.100  26.000 11.400  15.300 11.400  15.300 6.500  12.700 6.500  12.700 11.400  7.300 11.400  7.300 6.500 ;
            POLYGON 20.700 6.500  20.700 9.900  29.600 9.900  29.600 28.000  28.000 28.000  28.000 31.400  29.600 31.400  29.600 48.100  15.300 48.100  15.300 58.300  17.900 58.300  17.900 49.900  31.400 49.900  31.400 6.500 ;
            POLYGON 11.300 48.100  11.300 61.100  13.900 61.100  13.900 48.100 ;
    END

END OR4
MACRO AND4_X1
    CLASS CORE ;
    FOREIGN AND4_X1 0.0 0.0 ;
    ORIGIN 0.0 0.0 ;
    SIZE 32.400 BY 64.800 ;
    SITE CoreSite ;

    PIN GND
        DIRECTION INOUT ;
        USE GROUND ;
        PORT
            LAYER M1 ;
                RECT 0.000 1.100 32.400 3.700 ;
        END
    END GND

    PIN VDD
        DIRECTION INOUT ;
        USE POWER ;
        PORT
            LAYER M1 ;
                RECT 0.000 61.100 32.400 63.700 ;
        END
    END VDD

    PIN A
        DIRECTION INPUT ;
        USE SIGNAL ;
        PORT
            LAYER M2 ;
                RECT 1.000 28.000 4.400 31.400 ;
        END
    END A

    PIN B
        DIRECTION INPUT ;
        USE SIGNAL ;
        PORT
            LAYER M2 ;
                RECT 6.400 28.000 9.800 31.400 ;
        END
    END B

    PIN C
        DIRECTION INPUT ;
        USE SIGNAL ;
        PORT
            LAYER M2 ;
                RECT 11.800 28.000 15.200 31.400 ;
        END
    END C

    PIN D
        DIRECTION INPUT ;
        USE SIGNAL ;
        PORT
            LAYER M2 ;
                RECT 17.200 28.000 20.600 31.400 ;
        END
    END D

    PIN Y
        DIRECTION OUTPUT ;
        USE SIGNAL ;
        PORT
            LAYER M2 ;
                RECT 28.000 28.000 31.400 31.400 ;
        END
    END Y

    OBS
        LAYER M1 ;
            POLYGON 20.800 3.700  20.800 9.500  23.400 9.500  23.400 3.700 ;
            POLYGON 5.300 3.700  5.300 9.900  7.900 9.900  7.900 3.700 ;
            POLYGON 1.000 28.000  1.000 36.500  3.600 36.500  3.600 31.400  4.400 31.400  4.400 28.000 ;
            POLYGON 6.400 28.000  6.400 31.400  7.500 31.400  7.500 36.500  10.100 36.500  10.100 33.900  9.800 33.900  9.800 28.000 ;
            POLYGON 17.200 28.000  17.200 31.400  18.300 31.400  18.300 36.500  21.000 36.500  21.000 33.900  20.600 33.900  20.600 28.000 ;
            POLYGON 11.800 28.000  11.800 31.400  12.900 31.400  12.900 40.300  15.500 40.300  15.500 37.700  15.200 37.700  15.200 28.000 ;
            POLYGON 24.800 6.900  24.800 9.500  29.600 9.500  29.600 28.000  28.000 28.000  28.000 31.400  29.600 31.400  29.600 48.900  24.800 48.900  24.800 57.500  27.400 57.500  27.400 50.700  31.400 50.700  31.400 7.700  27.400 7.700  27.400 6.900 ;
            POLYGON 15.900 6.500  15.900 9.900  16.700 9.900  16.700 26.200  23.600 26.200  23.600 26.600  24.400 26.600  24.400 44.900  4.700 44.900  4.700 58.300  7.300 58.300  7.300 46.700  12.700 46.700  12.700 58.300  15.300 58.300  15.300 46.700  26.200 46.700  26.200 24.000  23.600 24.000  23.600 24.400  18.500 24.400  18.500 6.500 ;
            POLYGON 0.700 48.100  0.700 61.100  3.300 61.100  3.300 48.100 ;
            POLYGON 8.700 48.100  8.700 61.100  11.300 61.100  11.300 48.100 ;
            POLYGON 16.700 48.100  16.700 61.100  19.300 61.100  19.300 48.100 ;
            POLYGON 20.800 48.900  20.800 61.100  23.400 61.100  23.400 48.900 ;
    END

END AND4_X1
MACRO MUX2
    CLASS CORE ;
    FOREIGN MUX2 0.0 0.0 ;
    ORIGIN 0.0 0.0 ;
    SIZE 32.400 BY 64.800 ;
    SITE CoreSite ;

    PIN GND
        DIRECTION INOUT ;
        USE GROUND ;
        PORT
            LAYER M1 ;
                RECT 0.000 1.100 32.400 3.700 ;
        END
    END GND

    PIN VDD
        DIRECTION INOUT ;
        USE POWER ;
        PORT
            LAYER M1 ;
                RECT 0.000 61.100 32.400 63.700 ;
        END
    END VDD

    PIN S
        DIRECTION INPUT ;
        USE SIGNAL ;
        PORT
            LAYER M2 ;
                RECT 17.200 6.300 20.600 9.700 ;
        END
    END S

    PIN A
        DIRECTION INPUT ;
        USE SIGNAL ;
        PORT
            LAYER M2 ;
                RECT 1.000 27.900 4.400 31.300 ;
        END
    END A

    PIN B
        DIRECTION INPUT ;
        USE SIGNAL ;
        PORT
            LAYER M2 ;
                RECT 22.600 27.900 26.000 31.300 ;
        END
    END B

    PIN Y
        DIRECTION OUTPUT ;
        USE SIGNAL ;
        PORT
            LAYER M2 ;
                RECT 28.000 27.900 31.400 31.300 ;
        END
    END Y

    OBS
        LAYER M1 ;
            POLYGON 8.200 3.700  8.200 9.500  10.800 9.500  10.800 3.700 ;
            POLYGON 17.200 5.300  17.200 9.700  20.600 9.700  20.600 7.900  23.400 7.900  23.400 5.300 ;
            POLYGON 12.200 6.900  12.200 11.200  5.800 11.200  5.800 13.800  20.400 13.800  20.400 11.200  14.800 11.200  14.800 6.900 ;
            POLYGON 1.800 3.700  1.800 19.300  4.400 19.300  4.400 3.700 ;
            POLYGON 28.200 3.700  28.200 11.200  23.300 11.200  23.300 16.600  17.800 16.600  17.800 19.300  26.600 19.300  26.600 13.800  30.800 13.800  30.800 3.700 ;
            POLYGON 1.200 25.100  1.200 27.900  1.000 27.900  1.000 31.300  4.400 31.300  4.400 27.900  3.800 27.900  3.800 25.100 ;
            POLYGON 17.000 25.100  17.000 27.700  22.600 27.700  22.600 31.300  26.000 31.300  26.000 25.100 ;
            POLYGON 5.800 16.600  5.800 43.300  8.400 43.300  8.400 16.600 ;
            POLYGON 13.800 16.600  13.800 43.300  16.400 43.300  16.400 36.700  15.600 36.700  15.600 19.300  16.400 19.300  16.400 16.600 ;
            POLYGON 28.000 16.600  28.000 47.600  30.600 47.600  30.600 31.300  31.400 31.300  31.400 27.900  30.600 27.900  30.600 16.600 ;
            POLYGON 9.800 16.600  9.800 19.300  10.200 19.300  10.200 36.700  9.800 36.700  9.800 43.300  10.200 43.300  10.200 49.600  9.800 49.600  9.800 52.200  12.400 52.200  12.400 49.600  12.000 49.600  12.000 43.300  12.400 43.300  12.400 36.700  12.000 36.700  12.000 19.300  12.400 19.300  12.400 16.600 ;
            POLYGON 17.100 45.800  17.100 48.400  17.500 48.400  17.500 56.400  8.400 56.400  8.400 51.600  5.800 51.600  5.800 58.200  19.300 58.200  19.300 48.400  19.700 48.400  19.700 45.800 ;
            POLYGON 1.800 36.700  1.800 61.100  4.400 61.100  4.400 36.700 ;
            POLYGON 17.800 36.700  17.800 43.300  24.000 43.300  24.000 61.100  26.600 61.100  26.600 36.700 ;
    END

END MUX2
MACRO DFFRB
    CLASS CORE ;
    FOREIGN DFFRB 0.0 0.0 ;
    ORIGIN 0.0 0.0 ;
    SIZE 64.800 BY 64.800 ;
    SITE CoreSite ;

    PIN GND
        DIRECTION INOUT ;
        USE GROUND ;
        PORT
            LAYER M1 ;
                RECT 0.000 1.100 64.800 3.700 ;
        END
    END GND

    PIN VDD
        DIRECTION INOUT ;
        USE POWER ;
        PORT
            LAYER M1 ;
                RECT 0.000 61.100 64.800 63.700 ;
        END
    END VDD

    PIN D
        DIRECTION INPUT ;
        USE SIGNAL ;
        PORT
            LAYER M2 ;
                RECT 11.800 27.900 15.200 31.300 ;
        END
    END D

    PIN QB
        DIRECTION OUTPUT ;
        USE SIGNAL ;
        PORT
            LAYER M2 ;
                RECT 49.600 27.900 53.000 31.300 ;
        END
    END QB

    PIN RSTB
        DIRECTION INPUT ;
        USE SIGNAL ;
        PORT
            LAYER M2 ;
                RECT 55.000 27.900 58.400 31.300 ;
        END
    END RSTB

    PIN Q
        DIRECTION OUTPUT ;
        USE SIGNAL ;
        PORT
            LAYER M2 ;
                RECT 60.400 27.900 63.800 31.300 ;
        END
    END Q

    PIN CK
        DIRECTION INPUT ;
        USE CLOCK ;
        PORT
            LAYER M2 ;
                RECT 1.000 54.900 4.400 58.300 ;
        END
    END CK

    OBS
        LAYER M1 ;
            POLYGON 4.700 3.700  4.700 19.200  7.300 19.200  7.300 3.700 ;
            POLYGON 22.900 3.700  22.900 13.400  12.700 13.400  12.700 19.200  15.300 19.200  15.300 15.200  26.900 15.200  26.900 19.200  29.500 19.200  29.500 13.400  25.500 13.400  25.500 3.700 ;
            POLYGON 42.900 3.700  42.900 19.200  47.500 19.200  47.500 3.700 ;
            POLYGON 57.000 3.700  57.000 19.200  59.600 19.200  59.600 3.700 ;
            POLYGON 12.600 25.100  12.600 27.900  11.800 27.900  11.800 31.300  15.200 31.300  15.200 25.100 ;
            POLYGON 55.000 25.100  55.000 31.300  58.400 31.300  58.400 27.900  57.600 27.900  57.600 25.100 ;
            POLYGON 18.900 16.600  18.900 19.200  19.700 19.200  19.700 36.900  18.900 36.900  18.900 41.500  21.500 41.500  21.500 30.300  23.200 30.300  23.200 27.700  21.500 27.700  21.500 16.600 ;
            POLYGON 22.900 16.600  22.900 19.200  23.700 19.200  23.700 22.400  25.600 22.400  25.600 33.700  23.700 33.700  23.700 36.900  22.900 36.900  22.900 41.500  25.500 41.500  25.500 35.500  27.400 35.500  27.400 20.600  25.500 20.600  25.500 16.600 ;
            POLYGON 34.900 16.600  34.900 19.200  35.700 19.200  35.700 36.900  34.900 36.900  34.900 41.500  37.500 41.500  37.500 30.300  39.300 30.300  39.300 27.700  37.500 27.700  37.500 16.600 ;
            POLYGON 38.900 16.600  38.900 19.200  39.700 19.200  39.700 22.400  41.600 22.400  41.600 33.700  39.700 33.700  39.700 36.900  38.900 36.900  38.900 41.500  41.500 41.500  41.500 35.500  43.400 35.500  43.400 20.600  41.500 20.600  41.500 16.600 ;
            POLYGON 0.700 11.200  0.700 46.100  3.300 46.100  3.300 37.500  2.500 37.500  2.500 19.200  3.300 19.200  3.300 11.200 ;
            POLYGON 61.000 16.600  61.000 27.900  60.400 27.900  60.400 31.300  61.000 31.300  61.000 47.000  63.600 47.000  63.600 31.300  63.800 31.300  63.800 27.900  63.600 27.900  63.600 16.600 ;
            POLYGON 8.700 9.000  8.700 20.600  6.800 20.600  6.800 36.100  8.700 36.100  8.700 47.900  16.100 47.900  16.100 48.700  18.700 48.700  18.700 46.100  11.300 46.100  11.300 37.500  10.500 37.500  10.500 34.300  8.600 34.300  8.600 22.400  10.500 22.400  10.500 19.200  11.300 19.200  11.300 9.000 ;
            POLYGON 26.900 9.400  26.900 12.000  30.900 12.000  30.900 20.600  28.800 20.600  28.800 35.500  30.900 35.500  30.900 46.100  26.900 46.100  26.900 48.700  29.500 48.700  29.500 47.900  33.500 47.900  33.500 36.900  32.700 36.900  32.700 33.700  30.600 33.700  30.600 22.400  32.700 22.400  32.700 19.200  33.500 19.200  33.500 10.200  29.500 10.200  29.500 9.400 ;
            POLYGON 51.200 11.200  51.200 20.600  49.800 20.600  49.800 27.900  49.600 27.900  49.600 31.300  49.700 31.300  49.700 36.900  48.900 36.900  48.900 52.000  51.500 52.000  51.500 31.300  53.000 31.300  53.000 27.900  51.600 27.900  51.600 22.400  53.000 22.400  53.000 19.200  53.800 19.200  53.800 11.200 ;
            POLYGON 1.000 50.500  1.000 58.300  4.400 58.300  4.400 53.100  3.600 53.100  3.600 50.500 ;
            POLYGON 4.700 37.500  4.700 46.100  5.500 46.100  5.500 51.100  8.700 51.100  8.700 61.100  11.300 61.100  11.300 49.300  7.300 49.300  7.300 37.500 ;
            POLYGON 12.700 36.900  12.700 44.700  22.900 44.700  22.900 61.100  25.500 61.100  25.500 44.700  29.500 44.700  29.500 36.900  26.900 36.900  26.900 42.900  15.300 42.900  15.300 36.900 ;
            POLYGON 42.900 36.900  42.900 61.100  47.500 61.100  47.500 36.900 ;
            POLYGON 52.900 36.900  52.900 47.000  57.000 47.000  57.000 61.100  59.600 61.100  59.600 36.900 ;
    END

END DFFRB
MACRO DFF
    CLASS CORE ;
    FOREIGN DFF 0.0 0.0 ;
    ORIGIN 0.0 0.0 ;
    SIZE 64.800 BY 64.800 ;
    SITE CoreSite ;

    PIN GND
        DIRECTION INOUT ;
        USE GROUND ;
        PORT
            LAYER M1 ;
                RECT 0.000 1.100 64.800 3.700 ;
        END
    END GND

    PIN VDD
        DIRECTION INOUT ;
        USE POWER ;
        PORT
            LAYER M1 ;
                RECT 0.000 61.100 64.800 63.700 ;
        END
    END VDD

    PIN D
        DIRECTION INPUT ;
        USE SIGNAL ;
        PORT
            LAYER M2 ;
                RECT 11.800 27.900 15.200 31.300 ;
        END
    END D

    PIN QB
        DIRECTION OUTPUT ;
        USE SIGNAL ;
        PORT
            LAYER M2 ;
                RECT 55.000 27.900 58.400 31.300 ;
        END
    END QB

    PIN Q
        DIRECTION OUTPUT ;
        USE SIGNAL ;
        PORT
            LAYER M2 ;
                RECT 60.400 27.900 63.800 31.300 ;
        END
    END Q

    PIN CK
        DIRECTION INPUT ;
        USE CLOCK ;
        PORT
            LAYER M2 ;
                RECT 1.000 54.900 4.400 58.300 ;
        END
    END CK

    OBS
        LAYER M1 ;
            POLYGON 4.700 3.700  4.700 19.200  7.300 19.200  7.300 3.700 ;
            POLYGON 22.900 3.700  22.900 13.400  12.700 13.400  12.700 19.200  15.300 19.200  15.300 15.200  26.900 15.200  26.900 19.200  29.500 19.200  29.500 13.400  25.500 13.400  25.500 3.700 ;
            POLYGON 42.900 3.700  42.900 19.200  51.000 19.200  51.000 3.700 ;
            POLYGON 56.400 3.700  56.400 19.200  59.000 19.200  59.000 3.700 ;
            POLYGON 12.600 25.100  12.600 27.900  11.800 27.900  11.800 31.300  15.200 31.300  15.200 25.100 ;
            POLYGON 18.900 16.600  18.900 19.200  19.700 19.200  19.700 36.900  18.900 36.900  18.900 41.500  21.500 41.500  21.500 30.300  23.200 30.300  23.200 27.700  21.500 27.700  21.500 16.600 ;
            POLYGON 22.900 16.600  22.900 19.200  23.700 19.200  23.700 22.400  25.600 22.400  25.600 33.700  23.700 33.700  23.700 36.900  22.900 36.900  22.900 41.500  25.500 41.500  25.500 35.500  27.400 35.500  27.400 20.600  25.500 20.600  25.500 16.600 ;
            POLYGON 34.900 16.600  34.900 19.200  35.700 19.200  35.700 36.900  34.900 36.900  34.900 41.500  37.500 41.500  37.500 30.300  39.300 30.300  39.300 27.700  37.500 27.700  37.500 16.600 ;
            POLYGON 38.900 16.600  38.900 19.200  39.700 19.200  39.700 22.400  41.600 22.400  41.600 33.700  39.700 33.700  39.700 36.900  38.900 36.900  38.900 41.500  41.500 41.500  41.500 35.500  43.400 35.500  43.400 20.600  41.500 20.600  41.500 16.600 ;
            POLYGON 0.700 11.200  0.700 46.100  3.300 46.100  3.300 37.500  2.500 37.500  2.500 19.200  3.300 19.200  3.300 11.200 ;
            POLYGON 60.400 16.600  60.400 47.000  63.000 47.000  63.000 31.300  63.800 31.300  63.800 27.900  63.000 27.900  63.000 16.600 ;
            POLYGON 8.700 9.000  8.700 20.600  6.800 20.600  6.800 36.100  8.700 36.100  8.700 47.900  16.100 47.900  16.100 48.700  18.700 48.700  18.700 46.100  11.300 46.100  11.300 37.500  10.500 37.500  10.500 34.300  8.600 34.300  8.600 22.400  10.500 22.400  10.500 19.200  11.300 19.200  11.300 9.000 ;
            POLYGON 26.900 9.400  26.900 12.000  30.900 12.000  30.900 20.600  28.800 20.600  28.800 35.500  30.900 35.500  30.900 46.100  26.900 46.100  26.900 48.700  29.500 48.700  29.500 47.900  33.500 47.900  33.500 36.900  32.700 36.900  32.700 33.700  30.600 33.700  30.600 22.400  32.700 22.400  32.700 19.200  33.500 19.200  33.500 10.200  29.500 10.200  29.500 9.400 ;
            POLYGON 52.400 11.200  52.400 19.200  53.200 19.200  53.200 22.400  55.000 22.400  55.000 33.700  53.200 33.700  53.200 36.900  52.400 36.900  52.400 52.000  55.000 52.000  55.000 35.500  56.800 35.500  56.800 31.300  58.400 31.300  58.400 27.900  56.800 27.900  56.800 20.600  55.000 20.600  55.000 11.200 ;
            POLYGON 1.000 50.500  1.000 58.300  4.400 58.300  4.400 53.100  3.600 53.100  3.600 50.500 ;
            POLYGON 4.700 37.500  4.700 46.100  5.500 46.100  5.500 51.100  8.700 51.100  8.700 61.100  11.300 61.100  11.300 49.300  7.300 49.300  7.300 37.500 ;
            POLYGON 12.700 36.900  12.700 44.700  22.900 44.700  22.900 61.100  25.500 61.100  25.500 44.700  29.500 44.700  29.500 36.900  26.900 36.900  26.900 42.900  15.300 42.900  15.300 36.900 ;
            POLYGON 42.900 36.900  42.900 61.100  51.000 61.100  51.000 36.900 ;
            POLYGON 56.400 36.900  56.400 61.100  59.000 61.100  59.000 36.900 ;
    END

END DFF
MACRO DFFS
    CLASS CORE ;
    FOREIGN DFFS 0.0 0.0 ;
    ORIGIN 0.0 0.0 ;
    SIZE 64.800 BY 64.800 ;
    SITE CoreSite ;

    PIN GND
        DIRECTION INOUT ;
        USE GROUND ;
        PORT
            LAYER M1 ;
                RECT 0.000 1.100 64.800 3.700 ;
        END
    END GND

    PIN VDD
        DIRECTION INOUT ;
        USE POWER ;
        PORT
            LAYER M1 ;
                RECT 0.000 61.100 64.800 63.700 ;
        END
    END VDD

    PIN D
        DIRECTION INPUT ;
        USE SIGNAL ;
        PORT
            LAYER M2 ;
                RECT 11.800 27.900 15.200 31.300 ;
        END
    END D

    PIN QB
        DIRECTION OUTPUT ;
        USE SIGNAL ;
        PORT
            LAYER M2 ;
                RECT 49.600 27.900 53.000 31.300 ;
        END
    END QB

    PIN SET
        DIRECTION INPUT ;
        USE SIGNAL ;
        PORT
            LAYER M2 ;
                RECT 55.000 27.900 58.400 31.300 ;
        END
    END SET

    PIN Q
        DIRECTION OUTPUT ;
        USE SIGNAL ;
        PORT
            LAYER M2 ;
                RECT 60.400 27.900 63.800 31.300 ;
        END
    END Q

    PIN CK
        DIRECTION INPUT ;
        USE CLOCK ;
        PORT
            LAYER M2 ;
                RECT 1.000 54.900 4.400 58.300 ;
        END
    END CK

    OBS
        LAYER M1 ;
            POLYGON 4.700 3.700  4.700 19.200  7.300 19.200  7.300 3.700 ;
            POLYGON 22.900 3.700  22.900 13.400  12.700 13.400  12.700 19.200  15.300 19.200  15.300 15.200  26.900 15.200  26.900 19.200  29.500 19.200  29.500 13.400  25.500 13.400  25.500 3.700 ;
            POLYGON 42.900 3.700  42.900 19.200  47.500 19.200  47.500 3.700 ;
            POLYGON 57.000 3.700  57.000 16.600  52.900 16.600  52.900 19.200  59.600 19.200  59.600 3.700 ;
            POLYGON 12.600 25.100  12.600 27.900  11.800 27.900  11.800 31.300  15.200 31.300  15.200 25.100 ;
            POLYGON 55.000 25.100  55.000 31.300  58.400 31.300  58.400 27.900  57.600 27.900  57.600 25.100 ;
            POLYGON 18.900 16.600  18.900 19.200  19.700 19.200  19.700 36.900  18.900 36.900  18.900 41.500  21.500 41.500  21.500 30.300  23.200 30.300  23.200 27.700  21.500 27.700  21.500 16.600 ;
            POLYGON 22.900 16.600  22.900 19.200  23.700 19.200  23.700 22.400  25.600 22.400  25.600 33.700  23.700 33.700  23.700 36.900  22.900 36.900  22.900 41.500  25.500 41.500  25.500 35.500  27.400 35.500  27.400 20.600  25.500 20.600  25.500 16.600 ;
            POLYGON 34.900 16.600  34.900 19.200  35.700 19.200  35.700 36.900  34.900 36.900  34.900 41.500  37.500 41.500  37.500 30.300  39.300 30.300  39.300 27.700  37.500 27.700  37.500 16.600 ;
            POLYGON 38.900 16.600  38.900 19.200  39.700 19.200  39.700 22.400  41.600 22.400  41.600 33.700  39.700 33.700  39.700 36.900  38.900 36.900  38.900 41.500  41.500 41.500  41.500 35.500  43.400 35.500  43.400 20.600  41.500 20.600  41.500 16.600 ;
            POLYGON 0.700 11.200  0.700 46.100  3.300 46.100  3.300 37.500  2.500 37.500  2.500 19.200  3.300 19.200  3.300 11.200 ;
            POLYGON 61.000 16.600  61.000 27.900  60.400 27.900  60.400 31.300  61.000 31.300  61.000 47.000  63.600 47.000  63.600 31.300  63.800 31.300  63.800 27.900  63.600 27.900  63.600 16.600 ;
            POLYGON 8.700 9.000  8.700 20.600  6.800 20.600  6.800 36.100  8.700 36.100  8.700 47.900  16.100 47.900  16.100 48.700  18.700 48.700  18.700 46.100  11.300 46.100  11.300 37.500  10.500 37.500  10.500 34.300  8.600 34.300  8.600 22.400  10.500 22.400  10.500 19.200  11.300 19.200  11.300 9.000 ;
            POLYGON 26.900 9.400  26.900 12.000  30.900 12.000  30.900 20.600  28.800 20.600  28.800 35.500  30.900 35.500  30.900 46.100  26.900 46.100  26.900 48.700  29.500 48.700  29.500 47.900  33.500 47.900  33.500 36.900  32.700 36.900  32.700 33.700  30.600 33.700  30.600 22.400  32.700 22.400  32.700 19.200  33.500 19.200  33.500 10.200  29.500 10.200  29.500 9.400 ;
            POLYGON 48.900 11.200  48.900 19.200  49.700 19.200  49.700 27.900  49.600 27.900  49.600 31.300  51.100 31.300  51.100 52.000  53.700 52.000  53.700 36.900  52.900 36.900  52.900 31.300  53.000 31.300  53.000 27.900  51.500 27.900  51.500 11.200 ;
            POLYGON 1.000 50.500  1.000 58.300  4.400 58.300  4.400 53.100  3.600 53.100  3.600 50.500 ;
            POLYGON 4.700 37.500  4.700 46.100  5.500 46.100  5.500 51.100  8.700 51.100  8.700 61.100  11.300 61.100  11.300 49.300  7.300 49.300  7.300 37.500 ;
            POLYGON 12.700 36.900  12.700 44.700  22.900 44.700  22.900 61.100  25.500 61.100  25.500 44.700  29.500 44.700  29.500 36.900  26.900 36.900  26.900 42.900  15.300 42.900  15.300 36.900 ;
            POLYGON 42.900 36.900  42.900 61.100  47.500 61.100  47.500 36.900 ;
            POLYGON 57.000 36.900  57.000 61.100  59.600 61.100  59.600 36.900 ;
    END

END DFFS
MACRO RSLATCH
    CLASS CORE ;
    FOREIGN RSLATCH 0.0 0.0 ;
    ORIGIN 0.0 0.0 ;
    SIZE 27.000 BY 64.800 ;
    SITE CoreSite ;

    PIN GND
        DIRECTION INOUT ;
        USE GROUND ;
        PORT
            LAYER M1 ;
                RECT 0.000 1.100 27.000 3.700 ;
        END
    END GND

    PIN VDD
        DIRECTION INOUT ;
        USE POWER ;
        PORT
            LAYER M1 ;
                RECT 0.000 61.100 27.000 63.700 ;
        END
    END VDD

    PIN Q
        DIRECTION OUTPUT ;
        USE SIGNAL ;
        PORT
            LAYER M2 ;
                RECT 1.000 28.000 4.400 31.400 ;
        END
    END Q

    PIN R
        DIRECTION INPUT ;
        USE SIGNAL ;
        PORT
            LAYER M2 ;
                RECT 6.400 28.000 9.800 31.400 ;
        END
    END R

    PIN S
        DIRECTION INPUT ;
        USE SIGNAL ;
        PORT
            LAYER M2 ;
                RECT 17.200 28.000 20.600 31.400 ;
        END
    END S

    PIN QB
        DIRECTION OUTPUT ;
        USE SIGNAL ;
        PORT
            LAYER M2 ;
                RECT 22.600 28.000 26.000 31.400 ;
        END
    END QB

    OBS
        LAYER M1 ;
            POLYGON 4.900 3.700  4.900 19.600  7.500 19.600  7.500 3.700 ;
            POLYGON 12.900 3.700  12.900 19.600  15.500 19.600  15.500 3.700 ;
            POLYGON 20.900 3.700  20.900 19.600  23.500 19.600  23.500 3.700 ;
            POLYGON 6.400 28.000  6.400 31.400  10.100 31.400  10.100 36.500  12.700 36.500  12.700 28.000 ;
            POLYGON 17.200 28.000  17.200 33.900  14.100 33.900  14.100 36.500  20.600 36.500  20.600 28.000 ;
            POLYGON 8.900 11.000  8.900 21.100  1.000 21.100  1.000 44.700  6.700 44.700  6.700 56.300  9.300 56.300  9.300 42.900  2.800 42.900  2.800 31.400  4.400 31.400  4.400 28.000  2.800 28.000  2.800 22.900  11.500 22.900  11.500 11.000 ;
            POLYGON 16.900 16.200  16.900 22.900  24.200 22.900  24.200 28.000  22.600 28.000  22.600 31.400  24.200 31.400  24.200 42.900  19.100 42.900  19.100 56.300  26.000 56.300  26.000 53.700  21.700 53.700  21.700 44.700  26.000 44.700  26.000 21.100  19.500 21.100  19.500 16.200 ;
            POLYGON 12.900 46.100  12.900 61.100  15.500 61.100  15.500 46.100 ;
    END

END RSLATCH
MACRO MUXDFFRB
    CLASS CORE ;
    FOREIGN MUXDFFRB 0.0 0.0 ;
    ORIGIN 0.0 0.0 ;
    SIZE 97.200 BY 64.800 ;
    SITE CoreSite ;

    PIN GND
        DIRECTION INOUT ;
        USE GROUND ;
        PORT
            LAYER M1 ;
                RECT 0.000 1.100 97.200 3.700 ;
        END
    END GND

    PIN VDD
        DIRECTION INOUT ;
        USE POWER ;
        PORT
            LAYER M1 ;
                RECT 0.000 61.100 97.200 63.700 ;
        END
    END VDD

    PIN S
        DIRECTION INPUT ;
        USE SIGNAL ;
        PORT
            LAYER M2 ;
                RECT 17.200 6.300 20.600 9.700 ;
        END
    END S

    PIN A
        DIRECTION INPUT ;
        USE SIGNAL ;
        PORT
            LAYER M2 ;
                RECT 1.000 27.900 4.400 31.300 ;
        END
    END A

    PIN B
        DIRECTION INPUT ;
        USE SIGNAL ;
        PORT
            LAYER M2 ;
                RECT 22.600 27.900 26.000 31.300 ;
        END
    END B

    PIN QB
        DIRECTION OUTPUT ;
        USE SIGNAL ;
        PORT
            LAYER M2 ;
                RECT 82.000 27.900 85.400 31.300 ;
        END
    END QB

    PIN RSTB
        DIRECTION INPUT ;
        USE SIGNAL ;
        PORT
            LAYER M2 ;
                RECT 87.400 27.900 90.800 31.300 ;
        END
    END RSTB

    PIN Q
        DIRECTION OUTPUT ;
        USE SIGNAL ;
        PORT
            LAYER M2 ;
                RECT 92.800 27.900 96.200 31.300 ;
        END
    END Q

    PIN CK
        DIRECTION INPUT ;
        USE CLOCK ;
        PORT
            LAYER M2 ;
                RECT 33.400 54.900 36.800 58.300 ;
        END
    END CK

    OBS
        LAYER M1 ;
            POLYGON 8.200 3.700  8.200 9.500  10.800 9.500  10.800 3.700 ;
            POLYGON 17.200 5.300  17.200 9.700  20.600 9.700  20.600 7.900  23.400 7.900  23.400 5.300 ;
            POLYGON 12.200 6.900  12.200 11.200  5.800 11.200  5.800 13.800  20.400 13.800  20.400 11.200  14.800 11.200  14.800 6.900 ;
            POLYGON 37.100 3.700  37.100 19.200  39.700 19.200  39.700 3.700 ;
            POLYGON 55.300 3.700  55.300 13.400  45.100 13.400  45.100 19.200  47.700 19.200  47.700 15.200  59.300 15.200  59.300 19.200  61.900 19.200  61.900 13.400  57.900 13.400  57.900 3.700 ;
            POLYGON 75.300 3.700  75.300 19.200  79.900 19.200  79.900 3.700 ;
            POLYGON 89.400 3.700  89.400 19.200  92.000 19.200  92.000 3.700 ;
            POLYGON 1.800 3.700  1.800 19.300  4.400 19.300  4.400 3.700 ;
            POLYGON 28.200 3.700  28.200 11.200  23.300 11.200  23.300 16.600  17.800 16.600  17.800 19.300  26.600 19.300  26.600 13.800  30.800 13.800  30.800 3.700 ;
            POLYGON 1.200 25.100  1.200 27.900  1.000 27.900  1.000 31.300  4.400 31.300  4.400 27.900  3.800 27.900  3.800 25.100 ;
            POLYGON 17.000 25.100  17.000 27.700  22.600 27.700  22.600 31.300  26.000 31.300  26.000 25.100 ;
            POLYGON 87.400 25.100  87.400 31.300  90.800 31.300  90.800 27.900  90.000 27.900  90.000 25.100 ;
            POLYGON 51.300 16.600  51.300 19.200  52.100 19.200  52.100 36.900  51.300 36.900  51.300 41.500  53.900 41.500  53.900 30.300  55.600 30.300  55.600 27.700  53.900 27.700  53.900 16.600 ;
            POLYGON 55.300 16.600  55.300 19.200  56.100 19.200  56.100 22.400  58.000 22.400  58.000 33.700  56.100 33.700  56.100 36.900  55.300 36.900  55.300 41.500  57.900 41.500  57.900 35.500  59.800 35.500  59.800 20.600  57.900 20.600  57.900 16.600 ;
            POLYGON 67.300 16.600  67.300 19.200  68.100 19.200  68.100 36.900  67.300 36.900  67.300 41.500  69.900 41.500  69.900 30.300  71.700 30.300  71.700 27.700  69.900 27.700  69.900 16.600 ;
            POLYGON 71.300 16.600  71.300 19.200  72.100 19.200  72.100 22.400  74.000 22.400  74.000 33.700  72.100 33.700  72.100 36.900  71.300 36.900  71.300 41.500  73.900 41.500  73.900 35.500  75.800 35.500  75.800 20.600  73.900 20.600  73.900 16.600 ;
            POLYGON 5.800 16.600  5.800 43.300  8.400 43.300  8.400 16.600 ;
            POLYGON 13.800 16.600  13.800 43.300  16.400 43.300  16.400 36.700  15.600 36.700  15.600 19.300  16.400 19.300  16.400 16.600 ;
            POLYGON 33.100 11.200  33.100 46.100  35.700 46.100  35.700 37.500  34.900 37.500  34.900 19.200  35.700 19.200  35.700 11.200 ;
            POLYGON 93.400 16.600  93.400 27.900  92.800 27.900  92.800 31.300  93.400 31.300  93.400 47.000  96.000 47.000  96.000 31.300  96.200 31.300  96.200 27.900  96.000 27.900  96.000 16.600 ;
            POLYGON 41.100 9.000  41.100 20.600  39.200 20.600  39.200 36.100  41.100 36.100  41.100 47.900  50.100 47.900  50.100 48.700  52.700 48.700  52.700 46.100  43.700 46.100  43.700 37.500  42.900 37.500  42.900 34.300  41.000 34.300  41.000 22.400  42.900 22.400  42.900 19.200  43.700 19.200  43.700 9.000 ;
            POLYGON 59.300 9.400  59.300 12.000  63.300 12.000  63.300 20.600  61.200 20.600  61.200 35.500  63.300 35.500  63.300 46.100  59.300 46.100  59.300 48.700  61.900 48.700  61.900 47.900  65.900 47.900  65.900 36.900  65.100 36.900  65.100 33.700  63.000 33.700  63.000 22.400  65.100 22.400  65.100 19.200  65.900 19.200  65.900 10.200  61.900 10.200  61.900 9.400 ;
            POLYGON 83.600 11.200  83.600 20.600  82.200 20.600  82.200 27.900  82.000 27.900  82.000 31.300  82.100 31.300  82.100 36.900  81.300 36.900  81.300 52.000  83.900 52.000  83.900 31.300  85.400 31.300  85.400 27.900  84.000 27.900  84.000 22.400  85.400 22.400  85.400 19.200  86.200 19.200  86.200 11.200 ;
            POLYGON 9.800 16.600  9.800 19.300  10.200 19.300  10.200 36.700  9.800 36.700  9.800 43.300  10.200 43.300  10.200 49.600  9.800 49.600  9.800 52.200  12.400 52.200  12.400 49.600  12.000 49.600  12.000 43.300  12.400 43.300  12.400 36.700  12.000 36.700  12.000 19.300  12.400 19.300  12.400 16.600 ;
            POLYGON 17.100 45.800  17.100 48.400  17.500 48.400  17.500 56.400  8.400 56.400  8.400 51.600  5.800 51.600  5.800 58.200  19.300 58.200  19.300 48.400  19.700 48.400  19.700 45.800 ;
            POLYGON 33.400 50.500  33.400 58.300  36.800 58.300  36.800 53.100  36.000 53.100  36.000 50.500 ;
            POLYGON 28.000 16.600  28.000 59.700  30.600 59.700  30.600 16.600 ;
            POLYGON 1.800 36.700  1.800 61.100  4.400 61.100  4.400 36.700 ;
            POLYGON 17.800 36.700  17.800 43.300  24.000 43.300  24.000 61.100  26.600 61.100  26.600 36.700 ;
            POLYGON 37.100 37.500  37.100 46.100  37.900 46.100  37.900 51.100  41.100 51.100  41.100 61.100  43.700 61.100  43.700 49.300  39.700 49.300  39.700 37.500 ;
            POLYGON 45.100 36.900  45.100 44.700  55.300 44.700  55.300 61.100  57.900 61.100  57.900 44.700  61.900 44.700  61.900 36.900  59.300 36.900  59.300 42.900  47.700 42.900  47.700 36.900 ;
            POLYGON 75.300 36.900  75.300 61.100  79.900 61.100  79.900 36.900 ;
            POLYGON 85.300 36.900  85.300 47.000  89.400 47.000  89.400 61.100  92.000 61.100  92.000 36.900 ;
    END

END MUXDFFRB
MACRO BUF_X1
    CLASS CORE ;
    FOREIGN BUF_X1 0.0 0.0 ;
    ORIGIN 0.0 0.0 ;
    SIZE 16.200 BY 64.800 ;
    SITE CoreSite ;

    PIN GND
        DIRECTION INOUT ;
        USE GROUND ;
        PORT
            LAYER M1 ;
                RECT 0.000 1.100 16.200 3.700 ;
        END
    END GND

    PIN VDD
        DIRECTION INOUT ;
        USE POWER ;
        PORT
            LAYER M1 ;
                RECT 0.000 61.100 16.200 63.700 ;
        END
    END VDD

    PIN A
        DIRECTION INPUT ;
        USE SIGNAL ;
        PORT
            LAYER M2 ;
                RECT 1.000 28.000 4.400 31.400 ;
        END
    END A

    PIN Y
        DIRECTION OUTPUT ;
        USE SIGNAL ;
        PORT
            LAYER M2 ;
                RECT 11.800 28.000 15.200 31.400 ;
        END
    END Y

    OBS
        LAYER M1 ;
            POLYGON 6.100 3.700  6.100 9.900  8.700 9.900  8.700 3.700 ;
            POLYGON 1.000 28.000  1.000 36.500  3.600 36.500  3.600 31.400  4.400 31.400  4.400 28.000 ;
            POLYGON 2.100 6.500  2.100 13.300  6.500 13.300  6.500 44.900  0.700 44.900  0.700 58.300  3.300 58.300  3.300 46.700  8.300 46.700  8.300 36.500  10.100 36.500  10.100 33.900  8.300 33.900  8.300 11.500  4.700 11.500  4.700 6.500 ;
            POLYGON 10.100 6.500  10.100 9.900  13.400 9.900  13.400 28.000  11.800 28.000  11.800 31.400  13.400 31.400  13.400 48.100  8.700 48.100  8.700 58.300  11.300 58.300  11.300 49.900  15.200 49.900  15.200 6.500 ;
            POLYGON 4.700 48.100  4.700 61.100  7.300 61.100  7.300 48.100 ;
    END

END BUF_X1
MACRO BUFTH
    CLASS CORE ;
    FOREIGN BUFTH 0.0 0.0 ;
    ORIGIN 0.0 0.0 ;
    SIZE 32.400 BY 64.800 ;
    SITE CoreSite ;

    PIN GND
        DIRECTION INOUT ;
        USE GROUND ;
        PORT
            LAYER M1 ;
                RECT 0.000 1.100 32.400 3.700 ;
        END
    END GND

    PIN VDD
        DIRECTION INOUT ;
        USE POWER ;
        PORT
            LAYER M1 ;
                RECT 0.000 61.100 32.400 63.700 ;
        END
    END VDD

    PIN A
        DIRECTION INPUT ;
        USE SIGNAL ;
        PORT
            LAYER M2 ;
                RECT 6.400 28.000 9.800 31.400 ;
        END
    END A

    PIN Y
        DIRECTION OUTPUT ;
        USE SIGNAL ;
        PORT
            LAYER M2 ;
                RECT 28.000 28.000 31.400 31.400 ;
        END
    END Y

    OBS
        LAYER M1 ;
            POLYGON 19.500 3.700  19.500 12.700  18.700 12.700  18.700 15.300  21.300 15.300  21.300 3.700 ;
            POLYGON 11.500 8.300  11.500 19.600  14.100 19.600  14.100 8.300 ;
            POLYGON 22.700 3.700  22.700 17.000  15.500 17.000  15.500 19.600  25.300 19.600  25.300 3.700 ;
            POLYGON 6.400 28.000  6.400 34.400  9.000 34.400  9.000 31.400  9.800 31.400  9.800 28.000 ;
            POLYGON 7.500 16.200  7.500 22.800  11.400 22.800  11.400 35.800  7.500 35.800  7.500 45.000  10.100 45.000  10.100 37.600  13.200 37.600  13.200 34.400  25.300 34.400  25.300 31.800  13.200 31.800  13.200 21.000  10.100 21.000  10.100 16.200 ;
            POLYGON 26.700 16.200  26.700 50.100  29.300 50.100  29.300 31.400  31.400 31.400  31.400 28.000  29.300 28.000  29.300 16.200 ;
            POLYGON 11.500 39.900  11.500 56.500  14.100 56.500  14.100 39.900 ;
            POLYGON 18.700 46.400  18.700 49.000  19.500 49.000  19.500 57.900  18.100 57.900  18.100 51.400  15.500 51.400  15.500 57.900  10.100 57.900  10.100 51.400  7.500 51.400  7.500 59.700  21.300 59.700  21.300 46.400 ;
            POLYGON 3.200 5.100  3.200 61.100  5.000 61.100  5.000 6.900  7.500 6.900  7.500 11.700  10.100 11.700  10.100 6.900  15.500 6.900  15.500 10.900  18.100 10.900  18.100 5.100 ;
            POLYGON 15.500 39.900  15.500 45.000  22.700 45.000  22.700 61.100  25.300 61.100  25.300 39.900 ;
    END

END BUFTH
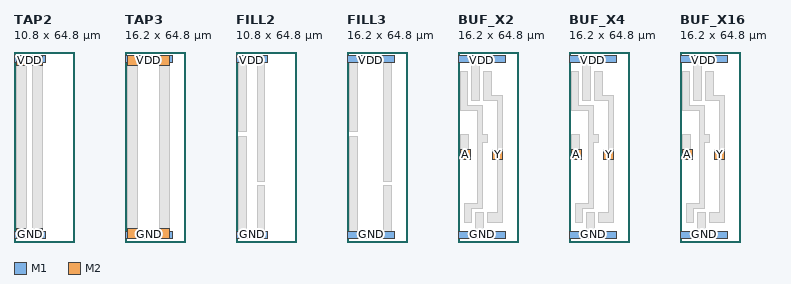
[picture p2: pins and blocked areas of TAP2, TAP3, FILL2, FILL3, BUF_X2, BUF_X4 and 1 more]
MACRO TAP2
    CLASS CORE ;
    FOREIGN TAP2 0.0 0.0 ;
    ORIGIN 0.0 0.0 ;
    SIZE 10.800 BY 64.800 ;
    SITE CoreSite ;

    PIN GND
        DIRECTION INOUT ;
        USE GROUND ;
        PORT
            LAYER M1 ;
                RECT 0.000 1.100 10.800 3.700 ;
            LAYER M2 ;
                RECT 1.000 1.100 4.400 4.500 ;
            LAYER M2 ;
                RECT 1.000 60.300 4.400 63.700 ;
        END
    END GND

    PIN VDD
        DIRECTION INOUT ;
        USE POWER ;
        PORT
            LAYER M1 ;
                RECT 0.000 61.100 10.800 63.700 ;
            LAYER M2 ;
                RECT 6.400 1.100 9.800 4.500 ;
            LAYER M2 ;
                RECT 6.400 60.300 9.800 63.700 ;
        END
    END VDD

    OBS
        LAYER M1 ;
            POLYGON 1.000 3.700  1.000 6.300  4.400 6.300  4.400 3.700 ;
            POLYGON 6.400 58.500  6.400 61.100  9.800 61.100  9.800 58.500 ;
        LAYER M2 ;
            POLYGON 1.000 4.500  1.000 60.300  4.400 60.300  4.400 4.500 ;
            POLYGON 6.400 4.500  6.400 60.300  9.800 60.300  9.800 4.500 ;
    END

END TAP2
MACRO TAP3
    CLASS CORE ;
    FOREIGN TAP3 0.0 0.0 ;
    ORIGIN 0.0 0.0 ;
    SIZE 16.200 BY 64.800 ;
    SITE CoreSite ;

    PIN GND
        DIRECTION INOUT ;
        USE GROUND ;
        PORT
            LAYER M1 ;
                RECT 0.000 1.100 16.200 3.700 ;
            LAYER M2 ;
                RECT 1.000 1.100 4.400 4.500 ;
            LAYER M2 ;
                RECT 1.000 60.300 4.400 63.700 ;
        END
    END GND

    PIN VDD
        DIRECTION INOUT ;
        USE POWER ;
        PORT
            LAYER M1 ;
                RECT 0.000 61.100 16.200 63.700 ;
            LAYER M2 ;
                RECT 11.800 1.100 15.200 4.500 ;
            LAYER M2 ;
                RECT 11.800 60.300 15.200 63.700 ;
        END
    END VDD

    OBS
        LAYER M1 ;
            POLYGON 1.000 3.700  1.000 6.300  4.400 6.300  4.400 3.700 ;
            POLYGON 11.800 58.500  11.800 61.100  15.200 61.100  15.200 58.500 ;
        LAYER M2 ;
            POLYGON 1.000 4.500  1.000 60.300  4.400 60.300  4.400 4.500 ;
            POLYGON 11.800 4.500  11.800 60.300  15.200 60.300  15.200 4.500 ;
    END

END TAP3
MACRO FILL2
    CLASS CORE ;
    FOREIGN FILL2 0.0 0.0 ;
    ORIGIN 0.0 0.0 ;
    SIZE 10.800 BY 64.800 ;
    SITE CoreSite ;

    PIN GND
        DIRECTION INOUT ;
        USE GROUND ;
        PORT
            LAYER M1 ;
                RECT 0.000 1.100 10.800 3.700 ;
        END
    END GND

    PIN VDD
        DIRECTION INOUT ;
        USE POWER ;
        PORT
            LAYER M1 ;
                RECT 0.000 61.100 10.800 63.700 ;
        END
    END VDD

    OBS
        LAYER M1 ;
            POLYGON 7.200 3.700  7.200 19.100  9.800 19.100  9.800 3.700 ;
            POLYGON 1.000 3.700  1.000 36.100  3.600 36.100  3.600 3.700 ;
            POLYGON 1.000 37.700  1.000 61.100  3.600 61.100  3.600 37.700 ;
            POLYGON 7.200 20.700  7.200 61.100  9.800 61.100  9.800 20.700 ;
    END

END FILL2
MACRO FILL3
    CLASS CORE ;
    FOREIGN FILL3 0.0 0.0 ;
    ORIGIN 0.0 0.0 ;
    SIZE 16.200 BY 64.800 ;
    SITE CoreSite ;

    PIN GND
        DIRECTION INOUT ;
        USE GROUND ;
        PORT
            LAYER M1 ;
                RECT 0.000 1.100 16.200 3.700 ;
        END
    END GND

    PIN VDD
        DIRECTION INOUT ;
        USE POWER ;
        PORT
            LAYER M1 ;
                RECT 0.000 61.100 16.200 63.700 ;
        END
    END VDD

    OBS
        LAYER M1 ;
            POLYGON 12.600 3.700  12.600 19.100  15.200 19.100  15.200 3.700 ;
            POLYGON 1.000 3.700  1.000 36.100  3.600 36.100  3.600 3.700 ;
            POLYGON 1.000 37.700  1.000 61.100  3.600 61.100  3.600 37.700 ;
            POLYGON 12.600 20.700  12.600 61.100  15.200 61.100  15.200 20.700 ;
    END

END FILL3
MACRO BUF_X2
    CLASS CORE ;
    FOREIGN BUF_X1 0.0 0.0 ;
    ORIGIN 0.0 0.0 ;
    SIZE 16.200 BY 64.800 ;
    SITE CoreSite ;

    PIN GND
        DIRECTION INOUT ;
        USE GROUND ;
        PORT
            LAYER M1 ;
                RECT 0.000 1.100 16.200 3.700 ;
        END
    END GND

    PIN VDD
        DIRECTION INOUT ;
        USE POWER ;
        PORT
            LAYER M1 ;
                RECT 0.000 61.100 16.200 63.700 ;
        END
    END VDD

    PIN A
        DIRECTION INPUT ;
        USE SIGNAL ;
        PORT
            LAYER M2 ;
                RECT 1.000 28.000 4.400 31.400 ;
        END
    END A

    PIN Y
        DIRECTION OUTPUT ;
        USE SIGNAL ;
        PORT
            LAYER M2 ;
                RECT 11.800 28.000 15.200 31.400 ;
        END
    END Y

    OBS
        LAYER M1 ;
            POLYGON 6.100 3.700  6.100 9.900  8.700 9.900  8.700 3.700 ;
            POLYGON 1.000 28.000  1.000 36.500  3.600 36.500  3.600 31.400  4.400 31.400  4.400 28.000 ;
            POLYGON 2.100 6.500  2.100 13.300  6.500 13.300  6.500 44.900  0.700 44.900  0.700 58.300  3.300 58.300  3.300 46.700  8.300 46.700  8.300 36.500  10.100 36.500  10.100 33.900  8.300 33.900  8.300 11.500  4.700 11.500  4.700 6.500 ;
            POLYGON 10.100 6.500  10.100 9.900  13.400 9.900  13.400 28.000  11.800 28.000  11.800 31.400  13.400 31.400  13.400 48.100  8.700 48.100  8.700 58.300  11.300 58.300  11.300 49.900  15.200 49.900  15.200 6.500 ;
            POLYGON 4.700 48.100  4.700 61.100  7.300 61.100  7.300 48.100 ;
    END

END BUF_X2
MACRO BUF_X4
    CLASS CORE ;
    FOREIGN BUF_X1 0.0 0.0 ;
    ORIGIN 0.0 0.0 ;
    SIZE 16.200 BY 64.800 ;
    SITE CoreSite ;

    PIN GND
        DIRECTION INOUT ;
        USE GROUND ;
        PORT
            LAYER M1 ;
                RECT 0.000 1.100 16.200 3.700 ;
        END
    END GND

    PIN VDD
        DIRECTION INOUT ;
        USE POWER ;
        PORT
            LAYER M1 ;
                RECT 0.000 61.100 16.200 63.700 ;
        END
    END VDD

    PIN A
        DIRECTION INPUT ;
        USE SIGNAL ;
        PORT
            LAYER M2 ;
                RECT 1.000 28.000 4.400 31.400 ;
        END
    END A

    PIN Y
        DIRECTION OUTPUT ;
        USE SIGNAL ;
        PORT
            LAYER M2 ;
                RECT 11.800 28.000 15.200 31.400 ;
        END
    END Y

    OBS
        LAYER M1 ;
            POLYGON 6.100 3.700  6.100 9.900  8.700 9.900  8.700 3.700 ;
            POLYGON 1.000 28.000  1.000 36.500  3.600 36.500  3.600 31.400  4.400 31.400  4.400 28.000 ;
            POLYGON 2.100 6.500  2.100 13.300  6.500 13.300  6.500 44.900  0.700 44.900  0.700 58.300  3.300 58.300  3.300 46.700  8.300 46.700  8.300 36.500  10.100 36.500  10.100 33.900  8.300 33.900  8.300 11.500  4.700 11.500  4.700 6.500 ;
            POLYGON 10.100 6.500  10.100 9.900  13.400 9.900  13.400 28.000  11.800 28.000  11.800 31.400  13.400 31.400  13.400 48.100  8.700 48.100  8.700 58.300  11.300 58.300  11.300 49.900  15.200 49.900  15.200 6.500 ;
            POLYGON 4.700 48.100  4.700 61.100  7.300 61.100  7.300 48.100 ;
    END

END BUF_X4
MACRO BUF_X16
    CLASS CORE ;
    FOREIGN BUF_X1 0.0 0.0 ;
    ORIGIN 0.0 0.0 ;
    SIZE 16.200 BY 64.800 ;
    SITE CoreSite ;

    PIN GND
        DIRECTION INOUT ;
        USE GROUND ;
        PORT
            LAYER M1 ;
                RECT 0.000 1.100 16.200 3.700 ;
        END
    END GND

    PIN VDD
        DIRECTION INOUT ;
        USE POWER ;
        PORT
            LAYER M1 ;
                RECT 0.000 61.100 16.200 63.700 ;
        END
    END VDD

    PIN A
        DIRECTION INPUT ;
        USE SIGNAL ;
        PORT
            LAYER M2 ;
                RECT 1.000 28.000 4.400 31.400 ;
        END
    END A

    PIN Y
        DIRECTION OUTPUT ;
        USE SIGNAL ;
        PORT
            LAYER M2 ;
                RECT 11.800 28.000 15.200 31.400 ;
        END
    END Y

    OBS
        LAYER M1 ;
            POLYGON 6.100 3.700  6.100 9.900  8.700 9.900  8.700 3.700 ;
            POLYGON 1.000 28.000  1.000 36.500  3.600 36.500  3.600 31.400  4.400 31.400  4.400 28.000 ;
            POLYGON 2.100 6.500  2.100 13.300  6.500 13.300  6.500 44.900  0.700 44.900  0.700 58.300  3.300 58.300  3.300 46.700  8.300 46.700  8.300 36.500  10.100 36.500  10.100 33.900  8.300 33.900  8.300 11.500  4.700 11.500  4.700 6.500 ;
            POLYGON 10.100 6.500  10.100 9.900  13.400 9.900  13.400 28.000  11.800 28.000  11.800 31.400  13.400 31.400  13.400 48.100  8.700 48.100  8.700 58.300  11.300 58.300  11.300 49.900  15.200 49.900  15.200 6.500 ;
            POLYGON 4.700 48.100  4.700 61.100  7.300 61.100  7.300 48.100 ;
    END

END BUF_X16
END LIBRARY
